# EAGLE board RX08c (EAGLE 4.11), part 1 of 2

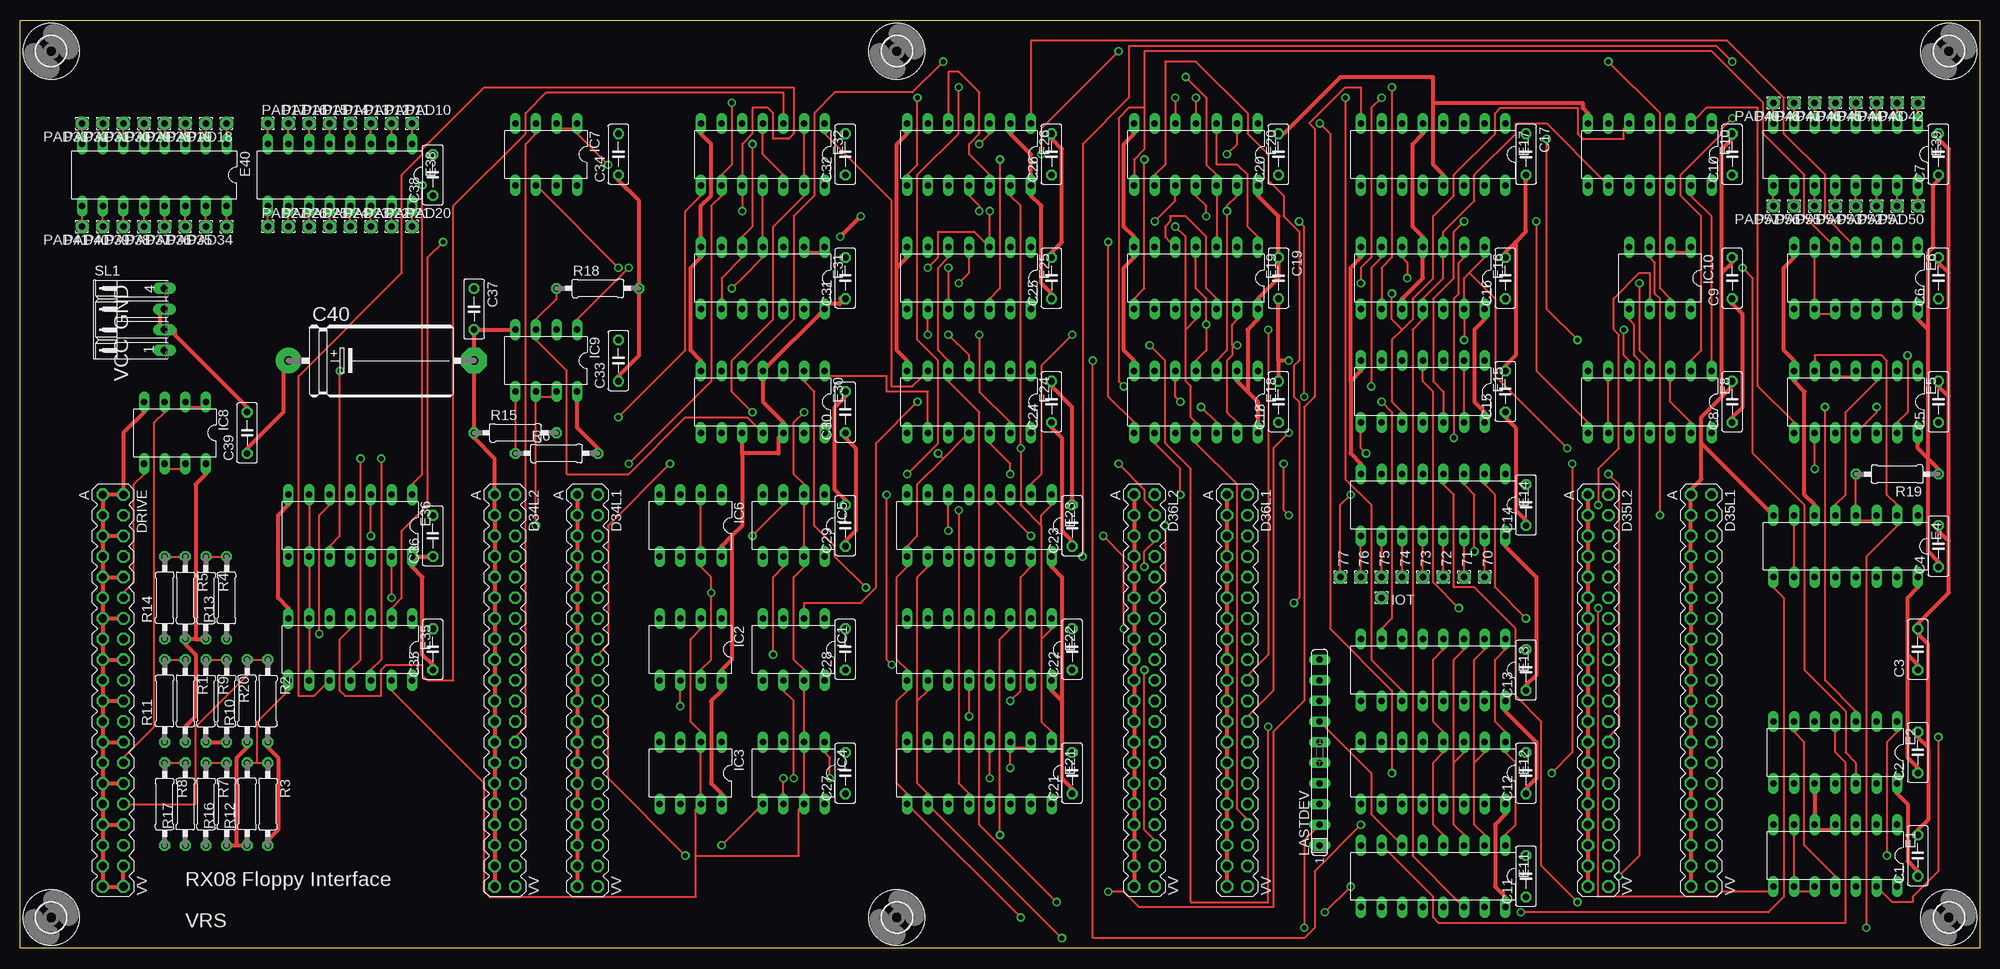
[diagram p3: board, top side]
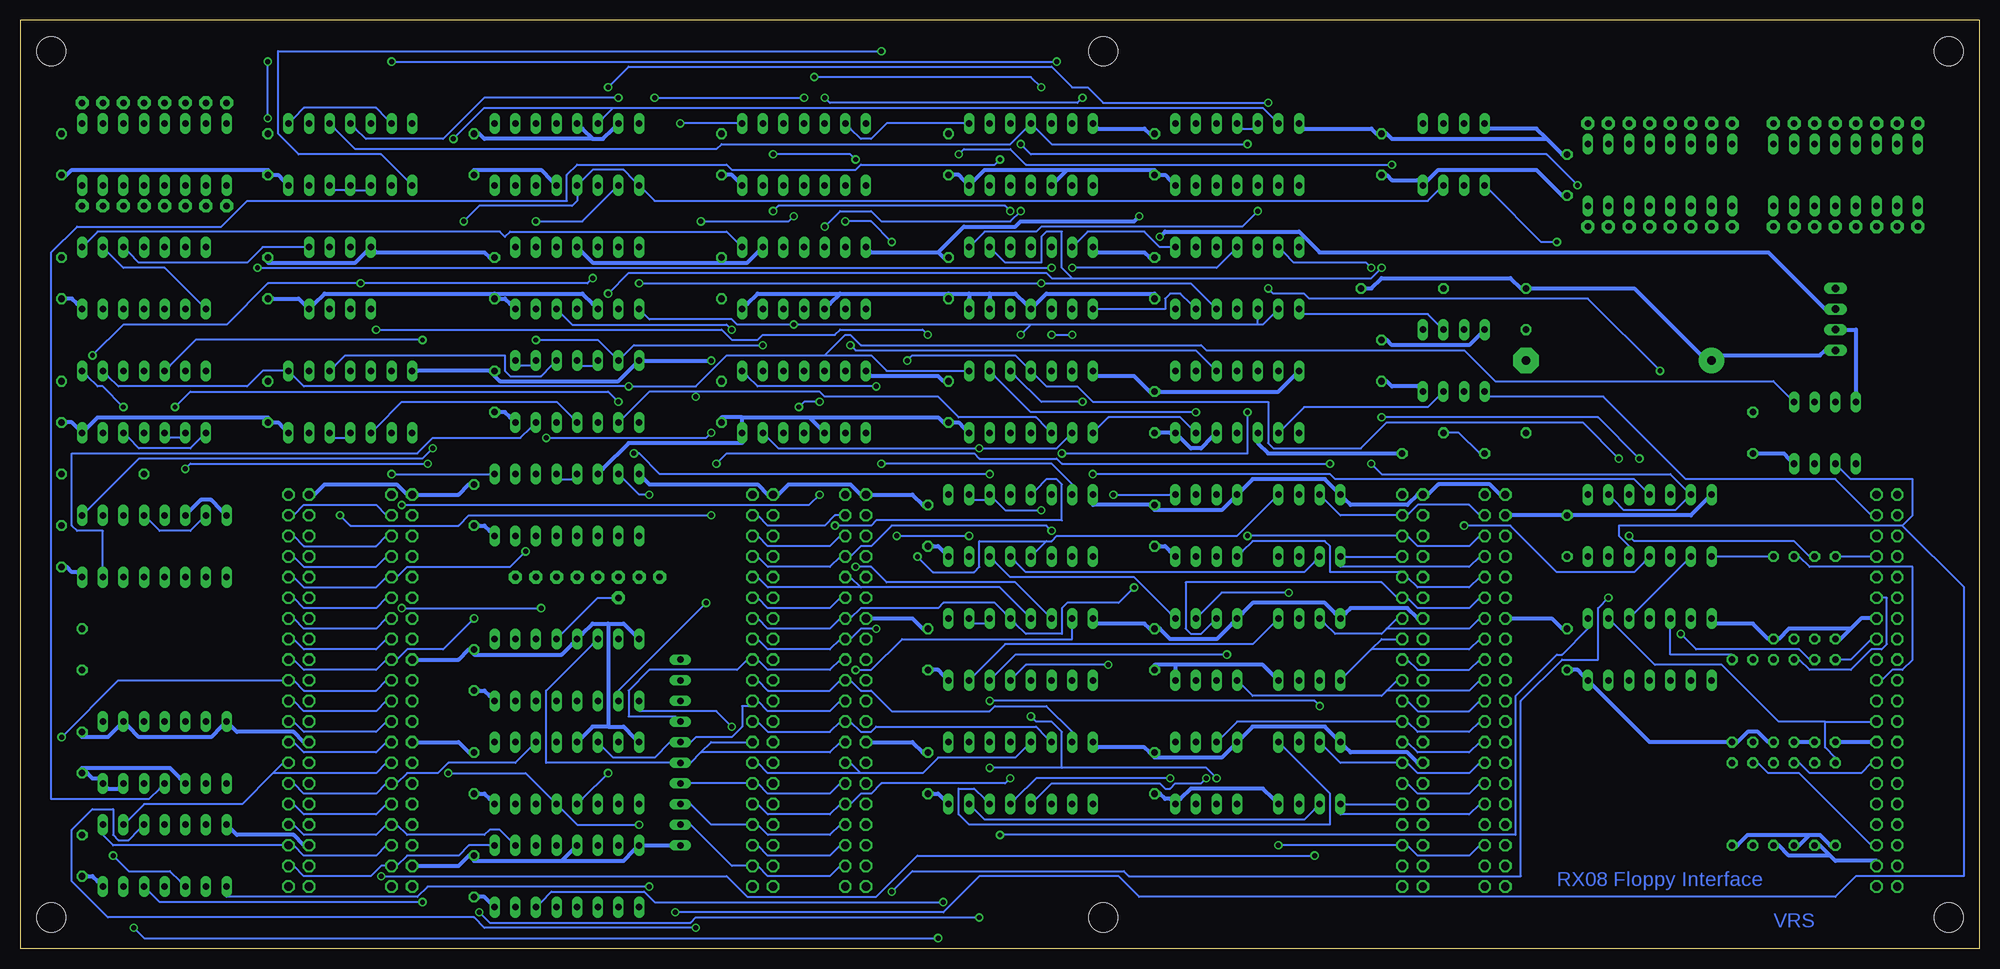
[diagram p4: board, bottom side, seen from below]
Size 241.3 x 114.3 mm. Coordinates in mm from the lower left corner, seen from the top.
Outline: 0,0 0,114.3 241.3,114.3 241.3,0 0,0
Copper layers (1*16): Top 0.035mm / dielectric 1.5mm / Bottom 0.035mm
Design rules "olimex10mil": minimum track width 10mil, minimum drill 24mil, track to track 10mil, track to pad 10mil, pad to pad 10mil, via to via 10mil, smd to smd 10mil, copper to edge 25mil, drill to drill 10mil, minimum pad ring 10mil, minimum via ring 8mil, stop-mask expansion 0mil, vias tented up to drill 0mil, thermal gap 10mil
Net classes: 1 supply: width 0.508 mm

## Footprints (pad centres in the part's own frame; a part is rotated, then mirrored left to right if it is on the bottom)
1,6/0,8 = drill 0.813 pad 1.6 octagon: 1 0,0
C050-025X075 = drill 0.813 octagon: 1 -2.54,0; 2 2.54,0
E22-9 = drill 1.016 pad 3.15 round: + -11.43,0 | drill 1.016 pad 3.15 octagon: - 11.43,0
DEC40PIN = drill 1.016 octagon: A -24.13,-1.27; AA 3.81,-1.27; B -24.13,1.27; BB 3.81,1.27; C -21.59,-1.27; CC 6.35,-1.27; D -21.59,1.27; DD 6.35,1.27; E -19.05,-1.27; EE 8.89,-1.27; F -19.05,1.27; FF 8.89,1.27; H -16.51,-1.27; HH 11.43,-1.27; J -16.51,1.27; JJ 11.43,1.27; K -13.97,-1.27; KK 13.97,-1.27; L -13.97,1.27; LL 13.97,1.27; M -11.43,-1.27; MM 16.51,-1.27; N -11.43,1.27; NN 16.51,1.27; P -8.89,-1.27; PP 19.05,-1.27; R -8.89,1.27; RR 19.05,1.27; S -6.35,-1.27; SS 21.59,-1.27; T -6.35,1.27; TT 21.59,1.27; U -3.81,-1.27; UU 24.13,-1.27; V -3.81,1.27; VV 24.13,1.27; W -1.27,-1.27; X -1.27,1.27; Y 1.27,-1.27; Z 1.27,1.27
DIL14 = drill 0.813 long: 1 -7.62,-3.81; 2 -5.08,-3.81; 3 -2.54,-3.81; 4 0,-3.81; 5 2.54,-3.81; 6 5.08,-3.81; 7 7.62,-3.81; 8 7.62,3.81; 9 5.08,3.81; 10 2.54,3.81; 11 0,3.81; 12 -2.54,3.81; 13 -5.08,3.81; 14 -7.62,3.81
DIL16 = drill 0.813 long: 1 -8.89,-3.81; 2 -6.35,-3.81; 3 -3.81,-3.81; 4 -1.27,-3.81; 5 1.27,-3.81; 6 3.81,-3.81; 7 6.35,-3.81; 8 8.89,-3.81; 9 8.89,3.81; 10 6.35,3.81; 11 3.81,3.81; 12 1.27,3.81; 13 -1.27,3.81; 14 -3.81,3.81; 15 -6.35,3.81; 16 -8.89,3.81
DIL08 = drill 0.813 long: 1 -3.81,-3.81; 2 -1.27,-3.81; 3 1.27,-3.81; 4 3.81,-3.81; 5 3.81,3.81; 6 1.27,3.81; 7 -1.27,3.81; 8 -3.81,3.81
SIL10 = drill 0.813 long: 1 -11.43,0; 2 -8.89,0; 3 -6.35,0; 4 -3.81,0; 5 -1.27,0; 6 1.27,0; 7 3.81,0; 8 6.35,0; 9 8.89,0; 10 11.43,0
0207/10 = drill 0.813 octagon: 1 -5.08,0; 2 5.08,0
04PA = drill 0.914 long: 1 -3.81,0; 2 -1.27,0; 3 1.27,0; 4 3.81,0
3,6 = hole 3.6: 0,0

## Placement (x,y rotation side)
70  [1,6/0,8]  180.34,45.72 270 top
71  [1,6/0,8]  177.8,45.72 270 top
72  [1,6/0,8]  175.26,45.72 270 top
73  [1,6/0,8]  172.72,45.72 270 top
74  [1,6/0,8]  170.18,45.72 270 top
75  [1,6/0,8]  167.64,45.72 270 top
76  [1,6/0,8]  165.1,45.72 270 top
77  [1,6/0,8]  162.56,45.72 270 top
C1  0.1  [C050-025X075]  233.68,11.43 90 top
C2  0.1  [C050-025X075]  233.68,24.13 90 top
C3  0.1  [C050-025X075]  233.68,36.83 90 top
C4  0.1  [C050-025X075]  236.22,49.53 90 top
C5  0.1  [C050-025X075]  236.22,67.31 90 top
C6  0.1  [C050-025X075]  236.22,82.55 90 top
C7  0.1  [C050-025X075]  236.22,97.79 90 top
C8  0.1  [C050-025X075]  210.82,67.31 90 top
C9  0.1  [C050-025X075]  210.82,82.55 90 top
C10  0.1  [C050-025X075]  210.82,97.79 90 top
C11  0.1  [C050-025X075]  185.42,8.89 90 top
C12  0.1  [C050-025X075]  185.42,21.59 90 top
C13  0.1  [C050-025X075]  185.42,34.29 90 top
C14  0.1  [C050-025X075]  185.42,54.61 90 top
C15  0.1  [C050-025X075]  182.88,68.58 90 top
C16  0.1  [C050-025X075]  182.88,82.55 90 top
C17  0.1  [C050-025X075]  185.42,97.79 270 top
C18  0.1  [C050-025X075]  154.94,67.31 90 top
C19  0.1  [C050-025X075]  154.94,82.55 270 top
C20  0.1  [C050-025X075]  154.94,97.79 90 top
C21  0.1  [C050-025X075]  129.54,21.59 90 top
C22  0.1  [C050-025X075]  129.54,36.83 90 top
C23  0.1  [C050-025X075]  129.54,52.07 90 top
C24  0.1  [C050-025X075]  127,67.31 90 top
C25  0.1  [C050-025X075]  127,82.55 90 top
C26  0.1  [C050-025X075]  127,97.79 90 top
C27  0.1  [C050-025X075]  101.6,21.59 90 top
C28  0.1  [C050-025X075]  101.6,36.83 90 top
C29  0.1  [C050-025X075]  101.6,52.07 90 top
C30  0.1  [C050-025X075]  101.6,66.04 90 top
C31  0.1  [C050-025X075]  101.6,82.55 90 top
C32  0.1  [C050-025X075]  101.6,97.79 90 top
C33  0.1  [C050-025X075]  73.66,72.39 90 top
C34  0.1  [C050-025X075]  73.66,97.79 90 top
C35  0.1  [C050-025X075]  50.8,36.83 90 top
C36  0.1  [C050-025X075]  50.8,50.8 90 top
C37  0.1  [C050-025X075]  55.88,78.74 270 top
C38  0.1  [C050-025X075]  50.8,95.25 90 top
C39  0.1  [C050-025X075]  27.94,63.5 90 top
C40  100uf  [E22-9]  44.45,72.39 0 top
D34L1  [DEC40PIN]  69.85,31.75 270 top
D34L2  [DEC40PIN]  59.69,31.75 270 top
D35L1  [DEC40PIN]  207.01,31.75 270 top
D35L2  [DEC40PIN]  194.31,31.75 270 top
D36L1  [DEC40PIN]  149.86,31.75 270 top
D36L2  [DEC40PIN]  138.43,31.75 270 top
DRIVE  [DEC40PIN]  11.43,31.75 270 top
E1  74LS10N  [DIL14]  223.52,11.43 180 top
E2  74LS74N  [DIL14]  223.52,24.13 180 top
E4  74LS161N  [DIL16]  224.79,49.53 180 top
E5  74LS00N  [DIL14]  226.06,67.31 180 top
E6  74LS00N  [DIL14]  226.06,82.55 180 top
E8  74LS10N  [DIL14]  200.66,67.31 180 top
E10  74LS10N  [DIL14]  200.66,97.79 180 top
E11  74LS138N  [DIL16]  173.99,8.89 180 top
E12  74LS138N  [DIL16]  173.99,21.59 180 top
E13  74LS138N  [DIL16]  173.99,34.29 180 top
E14  74LS138N  [DIL16]  173.99,54.61 180 top
E15  74LS00N  [DIL14]  172.72,68.58 180 top
E16  74LS74N  [DIL14]  172.72,82.55 180 top
E17  74LS76N  [DIL16]  173.99,97.79 180 top
E18  74LS74N  [DIL14]  144.78,67.31 180 top
E19  74LS74N  [DIL14]  144.78,82.55 180 top
E20  74HCT32N  [DIL14]  144.78,97.79 180 top
E21  74LS195N  [DIL16]  118.11,21.59 180 top
E22  74LS195N  [DIL16]  118.11,36.83 180 top
E23  74LS195N  [DIL16]  118.11,52.07 180 top
E24  74LS08N  [DIL14]  116.84,67.31 180 top
E25  74LS04N  [DIL14]  116.84,82.55 180 top
E26  74LS74N  [DIL14]  116.84,97.79 180 top
E30  74LS74N  [DIL14]  91.44,67.31 180 top
E31  74LS20N  [DIL14]  91.44,82.55 180 top
E32  74LS27N  [DIL14]  91.44,97.79 180 top
E35  74HCT02N  [DIL14]  40.64,36.83 180 top
E36  74HCT02N  [DIL14]  40.64,52.07 180 top
E38  SPARE  [DIL16]  39.37,95.25 180 top
E39  SPARE  [DIL16]  224.79,97.79 180 top
E40  SPARE  [DIL16]  16.51,95.25 180 top
IC1  DS75452N  [DIL08]  95.25,36.83 180 top
IC2  DS75452N  [DIL08]  82.55,36.83 180 top
IC3  DS75452N  [DIL08]  82.55,21.59 180 top
IC4  DS75452N  [DIL08]  95.25,21.59 180 top
IC5  DS75452N  [DIL08]  95.25,52.07 180 top
IC6  DS75452N  [DIL08]  82.55,52.07 180 top
IC7  DS75452N  [DIL08]  64.77,97.79 180 top
IC8  DS75452N  [DIL08]  19.05,63.5 180 top
IC9  DS75452N  [DIL08]  64.77,72.39 180 top
IC10  DS75452N  [DIL08]  201.93,82.55 180 top
IOT  [1,6/0,8]  167.64,43.18 270 top
LASTDEV  100  [SIL10]  160.02,24.13 90 top
PAD10  [1,6/0,8]  48.26,101.6 0 top
PAD11  [1,6/0,8]  45.72,101.6 0 top
PAD12  [1,6/0,8]  43.18,101.6 0 top
PAD13  [1,6/0,8]  40.64,101.6 0 top
PAD14  [1,6/0,8]  38.1,101.6 0 top
PAD15  [1,6/0,8]  35.56,101.6 0 top
PAD16  [1,6/0,8]  33.02,101.6 0 top
PAD17  [1,6/0,8]  30.48,101.6 0 top
PAD18  [1,6/0,8]  25.4,101.6 180 top
PAD19  [1,6/0,8]  22.86,101.6 180 top
PAD20  [1,6/0,8]  48.26,88.9 0 top
PAD21  [1,6/0,8]  45.72,88.9 0 top
PAD22  [1,6/0,8]  43.18,88.9 0 top
PAD23  [1,6/0,8]  40.64,88.9 0 top
PAD24  [1,6/0,8]  38.1,88.9 0 top
PAD25  [1,6/0,8]  35.56,88.9 0 top
PAD26  [1,6/0,8]  33.02,88.9 0 top
PAD27  [1,6/0,8]  30.48,88.9 0 top
PAD28  [1,6/0,8]  20.32,101.6 180 top
PAD29  [1,6/0,8]  17.78,101.6 180 top
PAD30  [1,6/0,8]  15.24,101.6 180 top
PAD31  [1,6/0,8]  12.7,101.6 180 top
PAD32  [1,6/0,8]  10.16,101.6 180 top
PAD33  [1,6/0,8]  7.62,101.6 180 top
PAD34  [1,6/0,8]  25.4,88.9 180 top
PAD35  [1,6/0,8]  22.86,88.9 180 top
PAD36  [1,6/0,8]  20.32,88.9 180 top
PAD37  [1,6/0,8]  17.78,88.9 180 top
PAD38  [1,6/0,8]  15.24,88.9 180 top
PAD39  [1,6/0,8]  12.7,88.9 180 top
PAD40  [1,6/0,8]  10.16,88.9 180 top
PAD41  [1,6/0,8]  7.62,88.9 180 top
PAD42  [1,6/0,8]  233.68,104.14 180 top
PAD43  [1,6/0,8]  231.14,104.14 180 top
PAD44  [1,6/0,8]  228.6,104.14 180 top
PAD45  [1,6/0,8]  226.06,104.14 180 top
PAD46  [1,6/0,8]  223.52,104.14 180 top
PAD47  [1,6/0,8]  220.98,104.14 180 top
PAD48  [1,6/0,8]  218.44,104.14 180 top
PAD49  [1,6/0,8]  215.9,104.14 180 top
PAD50  [1,6/0,8]  233.68,91.44 180 top
PAD51  [1,6/0,8]  231.14,91.44 180 top
PAD52  [1,6/0,8]  228.6,91.44 180 top
PAD53  [1,6/0,8]  226.06,91.44 180 top
PAD54  [1,6/0,8]  223.52,91.44 180 top
PAD55  [1,6/0,8]  220.98,91.44 180 top
PAD56  [1,6/0,8]  218.44,91.44 180 top
PAD57  [1,6/0,8]  215.9,91.44 180 top
R1  180  [0207/10]  20.32,30.48 270 top
R2  180  [0207/10]  30.48,30.48 270 top
R3  180  [0207/10]  30.48,17.78 270 top
R4  180  [0207/10]  22.86,43.18 270 top
R5  180  [0207/10]  20.32,43.18 270 top
R6  180  [0207/10]  66.04,60.96 0 top
R7  180  [0207/10]  22.86,17.78 270 top
R8  180  [0207/10]  17.78,17.78 270 top
R9  390  [0207/10]  22.86,30.48 270 top
R10  390  [0207/10]  27.94,30.48 90 top
R11  390  [0207/10]  17.78,30.48 90 top
R12  390  [0207/10]  27.94,17.78 90 top
R13  390  [0207/10]  25.4,43.18 90 top
R14  390  [0207/10]  17.78,43.18 90 top
R15  390  [0207/10]  60.96,63.5 0 top
R16  390  [0207/10]  25.4,17.78 90 top
R17  390  [0207/10]  20.32,17.78 90 top
R18  10K  [0207/10]  71.12,81.28 0 top
R19  10K  [0207/10]  231.14,58.42 180 top
R20  180  [0207/10]  25.4,30.48 270 top
SL1  [04PA]  17.78,77.47 90 top
U$1  [3,6]  237.49,3.81 0 top
U$2  [3,6]  237.49,110.49 0 top
U$3  [3,6]  3.81,110.49 0 top
U$4  [3,6]  3.81,3.81 0 top
U$5  [3,6]  107.95,110.49 0 top
U$6  [3,6]  107.95,3.81 0 top

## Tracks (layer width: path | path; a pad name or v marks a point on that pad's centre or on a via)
8/12  (via drill 0.61)
  Top 0.254: v170.81,82.55 170.81,84.45 170.18,85.09 E16.5 | v199.39,81.92 199.39,73.66 200.66,72.39 E8.4 | v232.41,73.03 232.41,66.04 231.14,64.77 E5.13
  Bottom 0.254: v170.81,82.55 171.45,81.92 v199.39,81.92 210.82,81.92 215.9,76.83 228.6,76.83 v232.41,73.03
8/12\  (via drill 0.61)
  Top 0.254: IC8.2 20.95,66.67 22.23,66.67 IC8.1 | v166.37,69.22 166.37,83.82 167.64,85.09 E16.6 | E10.13 205.74,92.71 208.28,90.17 208.28,72.39 E8.1
  Bottom 0.254: 142.24,73.03 154.31,73.03 158.12,69.22 v166.37,69.22 206.38,69.22 207.65,70.48 E8.1 208.91,71.12 211.46,71.12 213.36,69.22 229.24,69.22 230.5,70.48 E5.2 | 142.24,73.03 136.53,73.03 134.62,71.12 125.09,71.12 E24.1 | 142.24,73.03 139.7,75.56 139.06,75.56 137.79,74.3 95.89,74.3 95.25,73.66 63.5,73.66 59.69,69.85 25.4,69.85 23.5,67.94 IC8.1
ACB00\
  Bottom 0.254: IC6.3 80.64,55.24 78.74,53.34 71.75,53.34 D34L1.D 70.48,53.34 69.22,54.61 62.87,54.61 61.59,53.34 D34L2.D
ACB01\
  Bottom 0.254: D34L1.J 71.75,48.26 78.11,48.26 IC6.5 78.74,46.99 62.87,46.99 61.59,48.26 D34L2.J
ACB02\
  Bottom 0.254: IC1.3 94.61,40.01 95.89,38.73 97.16,38.73 97.79,39.37 97.79,45.09 73.66,45.09 71.75,43.18 D34L1.N 70.48,43.18 69.22,41.91 62.87,41.91 61.59,43.18 D34L2.N
ACB03\
  Bottom 0.254: 74.93,36.83 73.66,38.1 71.75,38.1 D34L1.T | 74.93,36.83 78.11,33.66 IC2.5 | 74.93,36.83 62.87,36.83 61.59,38.1 D34L2.T
ACB04\
  Bottom 0.254: 73.03,31.75 71.75,33.02 D34L1.X | 73.03,31.75 73.66,31.11 89.53,31.11 90.81,32.38 IC1.5 | 73.03,31.75 62.87,31.75 61.59,33.02 D34L2.X
ACB05\
  Bottom 0.254: IC4.3 93.34,26.04 91.44,27.94 71.75,27.94 D34L1.BB 70.48,27.94 69.22,26.67 62.87,26.67 61.59,27.94 D34L2.BB
ACB06\
  Bottom 0.254: IC3.3 80.64,24.77 78.74,22.86 71.75,22.86 D34L1.FF 70.48,22.86 69.22,21.59 62.87,21.59 61.59,22.86 D34L2.FF
ACB07\
  Bottom 0.254: D34L1.LL 71.75,17.78 78.11,17.78 IC3.5 78.74,16.51 62.87,16.51 61.59,17.78 D34L2.LL
ACB08\  (via drill 0.61)
  Top 0.254: v86.36,12.7 90.81,17.14 IC4.5
  Bottom 0.254: v86.36,12.7 71.75,12.7 D34L1.RR 70.48,12.7 69.22,11.43 62.87,11.43 61.59,12.7 D34L2.RR
ACB09\  (via drill 0.61)
  Top 0.254: v90.17,50.8 93.98,54.61 IC5.3
  Bottom 0.254: v90.17,50.8 71.75,50.8 D34L1.F 70.48,50.8 69.22,49.53 62.87,49.53 61.59,50.8 D34L2.F
ACB10\
  Bottom 0.254: IC5.5 90.81,48.9 89.53,50.16 80.64,50.16 80.01,49.53 80.01,46.35 71.12,46.35 D34L1.L 70.48,45.72 69.22,44.45 62.87,44.45 61.59,45.72 D34L2.L
ACB11\
  Bottom 0.254: 73.03,39.37 71.75,40.64 D34L1.R | 73.03,39.37 73.66,38.73 79.38,38.73 80.64,40.01 IC2.3 | 73.03,39.37 62.87,39.37 61.59,40.64 D34L2.R
ACCLEAR\
  Top 0.254: IC7.3 63.5,100.33 62.23,99.06 62.23,27.3 60.96,26.04 D34L2.DD
  Bottom 0.254: D34L1.DD 70.48,25.4 69.22,24.13 62.87,24.13 61.59,25.4 D34L2.DD
BAC00  (via drill 0.61)
  Top 0.254: v135.25,59.69 138.43,56.52 138.43,55.24 139.7,53.98 D36L2.D
  Bottom 0.254: v135.25,59.69 114.3,59.69 111.76,57.15 E23.7 | D36L1.D 150.5,53.34 149.22,52.07 142.24,52.07 140.97,53.34 140.34,53.34 D36L2.D
BAC01  (via drill 0.61)
  Top 0.254: v114.3,51.44 114.3,54.61 E23.6
  Bottom 0.254: v114.3,51.44 114.94,52.07 133.99,52.07 136.53,49.53 137.79,49.53 139.06,48.26 D36L2.J 140.34,48.26 141.6,46.99 149.22,46.99 150.5,48.26 D36L1.J
BAC02  (via drill 0.61)
  Top 0.254: v140.97,52.07 140.97,45.09 139.7,43.81 D36L2.N
  Bottom 0.254: v140.97,52.07 136.53,52.07 135.89,52.7 113.03,52.7 113.03,57.15 113.67,57.78 114.94,57.78 116.2,56.52 E23.5 | D36L1.N 150.5,43.18 149.22,41.91 141.6,41.91 140.34,43.18 D36L2.N
BAC03  (via drill 0.61)
  Top 0.254: v124.46,50.8 120.02,55.24 E23.4 | v133.35,50.8 135.89,48.26 v135.89,39.37
  Bottom 0.254: v133.35,50.8 v124.46,50.8 | v135.89,39.37 137.79,39.37 139.06,38.1 D36L2.T 140.34,38.1 141.6,36.83 149.22,36.83 150.5,38.1 D36L1.T
BAC04  (via drill 0.61)
  Top 0.254: v153.67,76.2 153.67,36.2 151.13,33.66 D36L1.X
  Bottom 0.254: E21.7 111.76,26.67 114.94,29.84 121.28,29.84 121.92,29.21 133.99,29.21 136.53,31.75 137.79,31.75 139.06,33.02 D36L2.X 140.34,33.02 141.6,31.75 149.22,31.75 150.5,33.02 D36L1.X | v153.67,76.2 154.31,76.83 173.35,76.83 174.62,78.11 E16.12
BAC05  (via drill 0.61)
  Top 0.254: v176.53,62.87 176.53,80.01 177.16,80.64 177.16,84.45 177.8,85.09 E16.2 | v156.21,63.5 154.31,61.59 154.31,31.75 151.13,28.57 D36L1.BB
  Bottom 0.254: E21.6 114.94,26.04 116.2,27.3 135.89,27.3 136.53,26.67 137.79,26.67 139.06,27.94 D36L2.BB 140.34,27.94 141.6,26.67 149.22,26.67 150.5,27.94 D36L1.BB | v176.53,62.87 156.84,62.87 v156.21,63.5
BAC06
  Bottom 0.254: 137.79,21.59 130.18,21.59 128.27,23.5 118.75,23.5 117.47,24.77 E21.5 | 137.79,21.59 139.06,22.86 D36L2.FF | 137.79,21.59 149.22,21.59 150.5,22.86 D36L1.FF
BAC07  (via drill 0.61)
  Top 0.254: v119.38,20.95 119.38,24.13 E21.4
  Bottom 0.254: v119.38,20.95 120.02,20.32 135.25,20.32 136.53,19.05 137.79,19.05 139.06,17.78 D36L2.LL 140.34,17.78 141.6,16.51 149.22,16.51 150.5,17.78 D36L1.LL
BAC08  (via drill 0.61)
  Top 0.254: v138.43,34.29 138.43,14.61 139.7,13.34 D36L2.RR
  Bottom 0.254: v138.43,34.29 136.53,34.29 132.72,38.1 111.76,38.1 111.76,39.37 E22.7 | D36L1.RR 150.5,12.7 149.22,11.43 141.6,11.43 140.34,12.7 D36L2.RR
BAC09  (via drill 0.61)
  Top 0.254: v138.43,46.99 138.43,48.9 139.7,50.16 D36L2.F
  Bottom 0.254: v138.43,46.99 136.53,46.99 134.62,45.09 118.75,45.09 114.94,41.27 E22.6 | D36L1.F 150.5,50.8 149.22,49.53 141.6,49.53 140.34,50.8 D36L2.F
BAC10
  Bottom 0.254: 137.79,44.45 120.65,44.45 117.47,41.27 E22.5 | 137.79,44.45 139.06,45.72 D36L2.L | 137.79,44.45 149.22,44.45 150.5,45.72 D36L1.L
BAC11  (via drill 0.61)
  Top 0.254: v104.14,44.45 100.33,48.26 100.33,49.53 97.79,52.07 97.79,68.58 96.52,69.85 E30.2
  Bottom 0.254: D36L1.R 150.5,40.64 149.22,39.37 141.6,39.37 140.34,40.64 D36L2.R 139.06,40.64 137.79,41.91 128.27,41.91 127.64,42.55 121.28,42.55 120.02,41.27 E22.4 118.75,40.01 117.47,38.73 113.03,38.73 113.03,41.91 112.39,42.55 106.05,42.55 v104.14,44.45
BINIT  (via drill 0.61)
  Top 0.254: v158.12,2.54 158.12,13.34 159.38,14.61 LASTDEV.2
  Bottom 0.254: LASTDEV.2 158.75,15.24 153.67,10.16 151.76,10.16 D36L1.TT 150.5,10.16 149.22,8.89 141.6,8.89 140.34,10.16 D36L2.TT | v158.12,2.54 184.15,2.54 185.42,3.81 230.5,3.81 234.95,8.26 234.95,14.61 232.41,17.14 229.87,17.14 229.87,13.97 229.24,13.34 227.97,13.34 226.69,14.61 E1.3
BIOP1
  Top 0.254: E11.6 169.54,13.34 166.37,16.51 166.37,21.59 160.66,27.3 LASTDEV.7
  Bottom 0.254: D36L2.V 140.34,35.56 141.6,34.29 149.22,34.29 150.5,35.56 D36L1.V 151.76,35.56 153.03,34.29 163.83,34.29 166.37,31.75 166.37,28.57 160.66,28.57 LASTDEV.7
BIOP2
  Bottom 0.254: E12.6 169.54,24.77 168.28,23.5 163.19,23.5 161.29,25.4 LASTDEV.6 158.75,25.4 158.12,26.04 153.67,26.04 152.4,27.3 152.4,29.84 151.13,29.84 D36L1.Z 150.5,30.48 149.22,29.21 141.6,29.21 140.34,30.48 D36L2.Z
BIOP4
  Bottom 0.254: 157.48,24.13 156.21,25.4 151.76,25.4 D36L1.DD | 157.48,24.13 158.75,22.86 LASTDEV.5 161.29,22.86 176.53,22.86 176.53,31.75 170.81,37.47 E13.6 | 157.48,24.13 141.6,24.13 140.34,25.4 D36L2.DD
BMB00
  Bottom 0.254: D35L2.D 196.22,53.34 197.49,54.61 206.38,54.61 207.65,53.34 D35L1.D
BMB01
  Bottom 0.254: D35L2.J 196.22,48.26 197.49,46.99 206.38,46.99 207.65,48.26 D35L1.J
BMB02
  Bottom 0.254: D35L2.N 196.22,43.18 197.49,41.91 206.38,41.91 207.65,43.18 D35L1.N
BMB03  (via drill 0.61)
  Top 0.254: v236.22,26.04 236.22,9.53 233.04,6.35 233.04,5.71 230.5,5.71 229.24,6.99 E1.13
  Bottom 0.254: v236.22,26.04 229.24,33.02 208.91,33.02 D35L1.X 207.65,33.02 206.38,31.75 197.49,31.75 196.22,33.02 D35L2.X
BMB03\
  Bottom 0.254: D35L2.T 196.22,38.1 197.49,36.83 206.38,36.83 207.65,38.1 D35L1.T
BMB04
  Bottom 0.254: 210.19,21.59 208.91,22.86 D35L1.FF | 210.19,21.59 214,17.78 226.06,17.78 227.97,15.88 E1.2 | 210.19,21.59 197.49,21.59 196.22,22.86 D35L2.FF
BMB04\
  Bottom 0.254: D35L2.BB 196.22,27.94 197.49,26.67 206.38,26.67 207.65,27.94 D35L1.BB
BMB05
  Bottom 0.254: E1.1 231.14,13.97 229.87,12.7 208.91,12.7 D35L1.RR 207.65,12.7 206.38,11.43 197.49,11.43 196.22,12.7 D35L2.RR
BMB05\
  Bottom 0.254: D35L2.LL 196.22,17.78 197.49,16.51 206.38,16.51 207.65,17.78 D35L1.LL
BMB06  (via drill 0.61)
  Top 0.254: v179.07,48.9 179.07,55.88 177.8,57.15 E14.3
  Bottom 0.254: v179.07,48.9 180.97,46.99 193.68,46.99 194.94,45.72 D35L2.L 196.22,45.72 197.49,44.45 206.38,44.45 207.65,45.72 D35L1.L
BMB06\
  Bottom 0.254: D35L2.F 196.22,50.8 197.49,49.53 206.38,49.53 207.65,50.8 D35L1.F
BMB07  (via drill 0.61)
  Top 0.254: v185.42,40.64 181.61,44.45 181.61,55.88 180.34,57.15 E14.2
  Bottom 0.254: v185.42,40.64 189.23,36.83 193.68,36.83 194.94,35.56 D35L2.V 196.22,35.56 197.49,34.29 206.38,34.29 207.65,35.56 D35L1.V
BMB07\
  Bottom 0.254: D35L2.R 196.22,40.64 197.49,39.37 206.38,39.37 207.65,40.64 D35L1.R
BMB08  (via drill 0.61)
  Top 0.254: v195.58,58.42 196.85,57.15 196.85,27.3 195.58,26.04 D35L2.DD
  Bottom 0.254: v195.58,58.42 183.51,58.42 E14.1 | D35L1.DD 207.65,25.4 206.38,24.13 197.49,24.13 196.22,25.4 D35L2.DD
BMB08\
  Bottom 0.254: D35L2.Z 196.22,30.48 197.49,29.21 206.38,29.21 207.65,30.48 D35L1.Z
BMB09
  Top 0.254: 176.53,22.86 176.53,15.24 177.8,13.97 E11.3 | 176.53,22.86 177.8,24.13 E12.3 | 176.53,22.86 176.53,35.56 177.8,36.83 E13.3
  Bottom 0.254: D35L1.JJ 207.65,20.32 206.38,19.05 197.49,19.05 196.22,20.32 D35L2.JJ 194.94,20.32 193.68,21.59 189.87,21.59 188.59,22.86 180.34,22.86 178.44,24.77 E12.3
BMB10
  Top 0.254: 179.07,22.86 179.07,15.24 180.34,13.97 E11.2 | 179.07,22.86 180.34,24.13 E12.2 | 179.07,22.86 179.07,35.56 180.34,36.83 E13.2
  Bottom 0.254: D35L1.NN 207.65,15.24 206.38,13.97 197.49,13.97 196.22,15.24 D35L2.NN 194.94,15.24 193.68,13.97 184.15,13.97 183.51,14.61 182.25,14.61 180.97,13.34 E11.2
BMB11
  Top 0.254: E11.1 182.88,13.97 184.15,15.24 184.15,22.86 182.88,24.13 E12.1 182.88,26.67 181.61,27.94 181.61,35.56 182.88,36.83 E13.1
  Bottom 0.254: E11.1 183.51,12.7 186.06,12.7 187.32,11.43 193.68,11.43 194.94,10.16 D35L2.TT 196.22,10.16 196.85,10.16 198.12,8.89 206.38,8.89 207.65,10.16 D35L1.TT
BRUN\
  Bottom 0.254: D34L2.JJ 61.59,20.32 62.87,19.05 69.22,19.05 70.48,20.32 D34L1.JJ
BTS1  (via drill 0.61)
  Top 0.254: 143.51,76.2 143.51,69.85 144.15,69.22 144.15,65.41 144.78,64.77 E18.11 144.78,62.23 149.86,57.15 149.86,17.14 151.13,15.88 D36L1.NN | 143.51,76.2 144.78,77.47 E19.11 | v118.11,90.81 118.11,91.44 116.84,92.71 E26.11 | v142.24,88.9 143.51,87.63 143.51,76.2
  Bottom 0.254: LASTDEV.3 158.75,17.78 156.21,15.24 151.76,15.24 D36L1.NN 150.5,15.24 149.22,13.97 141.6,13.97 140.34,15.24 D36L2.NN | v118.11,90.81 119.38,89.53 135.25,89.53 136.53,90.81 140.34,90.81 v142.24,88.9
BTS3
  Bottom 0.254: LASTDEV.4 158.75,20.32 151.76,20.32 D36L1.JJ 150.5,20.32 149.22,19.05 141.6,19.05 140.34,20.32 D36L2.JJ
CLK_BUF  (via drill 0.61)
  Top 0.254: E5.6 220.98,72.39 220.98,73.03 229.24,73.03 229.87,72.39 229.87,55.88 231.14,54.61 E4.2 231.14,52.07 227.33,48.26 v227.33,2.54 | 110.49,30.48 110.49,20.32 111.76,19.05 E21.10 112.39,17.14 v128.27,1.27 | 110.49,30.48 111.76,31.75 E22.10 | 110.49,30.48 110.49,45.72 111.76,46.99 E23.10
  Bottom 0.254: v227.33,2.54 226.06,1.27 v128.27,1.27
CLK_PARITY\  (via drill 0.61)
  Top 0.254: E5.5 224.16,70.48 225.43,70.48 E5.4 | v191.77,74.93 187.96,78.74 v187.96,99.69
  Bottom 0.254: 168.28,103.5 88.27,103.5 87,102.23 E32.6 | 168.28,103.5 169.54,102.23 E17.6 | v191.77,74.93 219.71,74.93 222.88,71.75 E5.5 | v187.96,99.69 184.15,103.5 168.28,103.5
DONE  (via drill 0.61)
  Top 0.254: E18.3 147.32,72.39 148.59,73.66 v148.59,90.81 148.59,91.44 149.86,92.71 E20.13 | E32.11 91.44,92.71 91.44,87.63 E31.4 91.44,85.09 88.9,82.55 v87.63,81.28 | v111.76,83.82 113.03,85.09 113.03,88.27 117.47,88.27 118.75,87 E25.3 119.38,87.63 v119.38,90.81 | v39.37,71.12 39.37,50.8 38.1,49.53 E36.10
  Bottom 0.254: v111.76,83.82 93.98,83.82 92.08,85.72 E31.4 | v148.59,90.81 147.96,91.44 120.02,91.44 v119.38,90.81 | v39.37,71.12 48.26,80.01 82.55,80.01 83.19,80.64 87,80.64 v87.63,81.28
DONE\  (via drill 0.61)
  Top 0.254: v115.57,81.92 116.84,83.19 116.84,85.09 E25.4 | v167.64,104.78 166.37,103.5 166.37,85.09 165.1,83.82 v165.1,81.92
  Bottom 0.254: E31.12 94.61,79.38 97.16,81.92 v115.57,81.92 v165.1,81.92 | v167.64,104.78 184.15,104.78 189.23,99.69 198.75,99.69 200.03,100.97 E10.4
DONE_FF  (via drill 0.61)
  Top 0.254: v142.88,55.88 142.88,59.05 139.7,62.23 E18.9 | v194.31,54.61 194.31,59.05 196.85,61.59 196.85,75.56 196.22,76.2 196.22,80.01 199.39,83.19 200.66,83.19 200.66,80.01 IC10.6
  Bottom 0.254: v142.88,55.88 144.15,54.61 v194.31,54.61
DONE_SKIP\  (via drill 0.61)
  Top 0.254: v135.89,69.22 135.25,69.85 135.25,102.23 136.53,103.5 138.43,103.5 | 138.43,103.5 138.43,98.42 137.16,97.16 137.16,95.25 E20.8 | 138.43,103.5 138.43,110.49 208.28,110.49 214.63,104.14 214.63,100.33 219.71,95.25 219.71,90.17 222.88,87 E6.5
  Bottom 0.254: v135.89,69.22 150.5,69.22 151.76,70.48 E18.1
ENB_BUF_LD\  (via drill 0.61)
  Top 0.254: E32.2 96.52,100.33 96.52,95.25 E32.13 96.52,92.71 92.71,88.9 92.71,77.47 87.63,72.39 87.63,68.58 v90.17,66.04 | v184.78,4.45 215.26,4.45 217.17,6.35 217.17,43.18 215.9,44.45 E4.9 | v123.19,3.81 109.86,17.14 E21.9 109.22,19.05 107.95,20.32 107.95,30.48 109.22,31.75 E22.9 109.22,34.29 107.95,35.56 107.95,45.72 109.22,46.99 E23.9 109.22,49.53 110.49,50.8 110.49,57.15 113.67,60.33 | 113.67,60.33 116.2,62.87 E24.11 | 113.67,60.33 v113.03,60.96
  Bottom 0.254: v184.78,4.45 183.51,3.17 158.75,3.17 158.12,3.81 v123.19,3.81 | v90.17,66.04 90.17,60.96 v113.03,60.96
ERR_SKIP\
  Top 0.254: E6.4 225.43,87 222.25,90.17 222.25,95.25 217.17,100.33 217.17,104.78 210.19,111.76 124.46,111.76 124.46,102.87 E26.1
  Bottom 0.254: E26.1 125.09,101.6 134.62,101.6 136.53,99.69 137.79,99.69 139.06,100.97 E20.6
ERROR  (via drill 0.61)
  Top 0.254: v49.53,93.98 49.53,58.42 48.26,57.15 E36.1 | v118.11,99.06 119.38,100.33 E26.3
  Bottom 0.254: v49.53,93.98 53.34,97.79 116.84,97.79 v118.11,99.06
GND  (via drill 0.61)
  Top 0.508: C39.2 27.94,66.67 19.05,75.56 19.05,76.2 SL1.2 17.14,76.83 17.14,78.11 SL1.3 | 26.67,12.7 27.3,12.7 R12.1 | 26.67,12.7 26.04,12.7 R16.1 | 26.67,12.7 26.67,23.5 27.94,24.77 R10.1 | DRIVE.MM 10.16,14.61 10.16,13.34 DRIVE.PP 10.16,12.06 10.16,10.79 DRIVE.SS 10.16,9.53 10.16,8.26 DRIVE.UU 10.79,7.62 12.06,7.62 DRIVE.VV 12.7,8.26 12.7,9.53 DRIVE.TT | DRIVE.NN 12.06,15.24 10.79,15.24 DRIVE.MM | DRIVE.MM 10.16,15.88 10.16,17.14 DRIVE.KK 10.16,18.41 10.16,19.68 DRIVE.HH | DRIVE.JJ 12.06,20.32 10.79,20.32 DRIVE.HH | DRIVE.HH 10.16,20.95 10.16,22.23 DRIVE.EE 10.16,23.5 10.16,24.77 DRIVE.CC | DRIVE.CC 10.16,26.04 10.16,27.3 DRIVE.AA 10.16,28.57 10.16,29.84 DRIVE.Y | DRIVE.Z 12.06,30.48 10.79,30.48 DRIVE.Y | DRIVE.Y 10.16,31.11 10.16,32.38 DRIVE.W 10.16,33.66 10.16,34.92 DRIVE.U | DRIVE.V 12.06,35.56 10.79,35.56 DRIVE.U | DRIVE.U 10.16,36.2 10.16,37.47 DRIVE.S 10.16,38.73 10.16,40.01 DRIVE.P | DRIVE.P 10.16,41.27 10.16,42.55 DRIVE.M 10.16,43.81 10.16,45.09 DRIVE.K | DRIVE.L 12.06,45.72 10.79,45.72 DRIVE.K | DRIVE.K 10.16,46.35 10.16,47.62 DRIVE.H 10.16,48.9 10.16,50.16 DRIVE.E | DRIVE.F 12.06,50.8 10.79,50.8 DRIVE.E | DRIVE.E 10.16,51.44 10.16,52.7 DRIVE.C 10.16,53.98 10.16,55.24 DRIVE.A 10.79,55.88 12.06,55.88 DRIVE.B 12.7,56.52 12.7,63.5 15.24,66.04 IC8.4 | DRIVE.DD 12.06,25.4 10.79,25.4 DRIVE.CC | DRIVE.R 12.06,40.64 10.79,40.64 DRIVE.P | E30.7 83.82,72.39 82.55,73.66 82.55,83.82 83.82,85.09 E31.7 83.82,87.63 83.82,91.44 85.09,92.71 85.09,99.06 83.82,100.33 E32.7 | 107.95,83.82 109.22,85.09 E25.7 | 107.95,83.82 107.95,73.66 109.22,72.39 E24.7 | 107.95,83.82 107.95,99.06 109.22,100.33 E26.7
  Top 0.508: D34L1.A 68.58,55.24 68.58,53.98 D34L1.C 68.58,52.7 68.58,51.44 D34L1.E 68.58,50.16 68.58,48.9 D34L1.H 68.58,47.62 68.58,46.35 D34L1.K 68.58,45.09 68.58,43.81 D34L1.M 68.58,42.55 68.58,41.27 D34L1.P 68.58,40.01 68.58,38.73 D34L1.S 68.58,37.47 68.58,36.2 D34L1.U 68.58,34.92 68.58,33.66 D34L1.W 68.58,32.38 68.58,31.11 D34L1.Y 68.58,29.84 68.58,28.57 D34L1.AA 68.58,27.3 68.58,26.04 D34L1.CC 68.58,24.77 68.58,23.5 D34L1.EE 68.58,22.23 68.58,20.95 D34L1.HH 68.58,19.68 68.58,18.41 D34L1.KK 68.58,17.14 68.58,15.88 D34L1.MM 68.58,14.61 68.58,13.34 D34L1.PP 68.58,12.06 68.58,10.79 D34L1.SS 68.58,9.53 68.58,8.26 D34L1.UU | IC9.4 60.33,76.2 56.52,76.2 C37.2 55.88,75.56 55.88,73.66 C40.- 55.88,71.12 55.88,64.14 R15.1 55.88,62.87 58.42,60.33 58.42,56.52 D34L2.A 58.42,55.24 58.42,53.98 D34L2.C 58.42,52.7 58.42,51.44 D34L2.E 58.42,50.16 58.42,48.9 D34L2.H 58.42,47.62 58.42,46.35 D34L2.K 58.42,45.09 58.42,43.81 D34L2.M 58.42,42.55 58.42,41.27 D34L2.P 58.42,40.01 58.42,38.73 D34L2.S 58.42,37.47 58.42,36.2 D34L2.U 58.42,34.92 58.42,33.66 D34L2.W 58.42,32.38 58.42,31.11 D34L2.Y 58.42,29.84 58.42,28.57 D34L2.AA 58.42,27.3 58.42,26.04 D34L2.CC 58.42,24.77 58.42,23.5 D34L2.EE 58.42,22.23 58.42,20.95 D34L2.HH 58.42,19.68 58.42,18.41 D34L2.KK 58.42,17.14 58.42,15.88 D34L2.MM 58.42,14.61 58.42,13.34 D34L2.PP 58.42,12.06 58.42,10.79 D34L2.SS 58.42,9.53 58.42,8.26 D34L2.UU | C30.2 101.6,67.94 100.33,66.67 100.33,56.52 101.6,55.24 C29.2 | E35.7 33.02,41.91 31.75,43.18 31.75,53.34 33.02,54.61 E36.7 | 154.94,72.39 154.94,79.38 C19.2
  Top 0.508: 154.94,72.39 154.94,70.48 C18.2 | 163.83,69.85 163.83,60.96 165.1,59.69 E14.8 | 163.83,69.85 165.1,71.12 E15.7 | 163.83,69.85 163.83,83.82 165.1,85.09 E16.7 | v156.21,72.39 154.94,72.39 | D36L1.UU 148.59,8.26 148.59,9.53 D36L1.SS 148.59,10.79 148.59,12.06 D36L1.PP 148.59,13.34 148.59,14.61 D36L1.MM 148.59,15.88 148.59,17.14 D36L1.KK 148.59,18.41 148.59,19.68 D36L1.HH 148.59,20.95 148.59,22.23 D36L1.EE 148.59,23.5 148.59,24.77 D36L1.CC 148.59,26.04 148.59,27.3 D36L1.AA 148.59,28.57 148.59,29.84 D36L1.Y 148.59,31.11 148.59,32.38 D36L1.W 148.59,33.66 148.59,34.92 D36L1.U 148.59,36.2 148.59,37.47 D36L1.S 148.59,38.73 148.59,40.01 D36L1.P 148.59,41.27 148.59,42.55 D36L1.M 148.59,43.81 148.59,45.09 D36L1.K 148.59,46.35 148.59,47.62 D36L1.H 148.59,48.9 148.59,50.16 D36L1.E 148.59,51.44 148.59,52.7 D36L1.C 148.59,53.98 148.59,55.24 D36L1.A | D36L2.UU 137.16,8.26 137.16,9.53 D36L2.SS 137.16,10.79 137.16,12.06 D36L2.PP 137.16,13.34 137.16,14.61 D36L2.MM 137.16,15.88 137.16,17.14 D36L2.KK 137.16,18.41 137.16,19.68 D36L2.HH 137.16,20.95 137.16,22.23 D36L2.EE 137.16,23.5 137.16,24.77 D36L2.CC 137.16,26.04 137.16,27.3 D36L2.AA 137.16,28.57 137.16,29.84 D36L2.Y 137.16,31.11 137.16,32.38 D36L2.W 137.16,33.66 137.16,34.92 D36L2.U 137.16,36.2 137.16,37.47 D36L2.S 137.16,38.73 137.16,40.01 D36L2.P 137.16,41.27 137.16,42.55 D36L2.M 137.16,43.81 137.16,45.09 D36L2.K 137.16,46.35 137.16,47.62 D36L2.H 137.16,48.9 137.16,50.16 D36L2.E 137.16,51.44 137.16,52.7 D36L2.C 137.16,53.98 137.16,55.24 D36L2.A | C26.2 127,99.69 128.27,98.42 128.27,87 127,85.72 C25.2
  Top 0.508: E20.7 137.16,100.33 135.89,99.06 135.89,88.9 137.16,87.63 E19.7 137.16,85.09 135.89,83.82 135.89,73.66 137.16,72.39 E18.7 | C24.2 127,69.22 129.54,66.67 129.54,55.24 C23.2 | 234.95,24.77 234.95,15.88 233.68,14.61 C1.2 | 234.95,24.77 233.68,26.04 C2.2 | 234.95,24.77 234.95,37.47 233.68,38.73 C3.2 233.68,40.01 237.49,43.81 237.49,50.16 | 237.49,50.16 236.22,51.44 C4.2 | 237.49,67.94 236.22,69.22 C5.2 | 237.49,50.16 237.49,67.94 | 237.49,83.19 236.22,84.45 C6.2 | 237.49,67.94 237.49,83.19 | 237.49,83.19 237.49,98.42 236.22,99.69 C7.2 | D35L2.UU 193.04,8.26 193.04,9.53 D35L2.SS 193.04,10.79 193.04,12.06 D35L2.PP 193.04,13.34 193.04,14.61 D35L2.MM 193.04,15.88 193.04,17.14 D35L2.KK 193.04,18.41 193.04,19.68 D35L2.HH 193.04,20.95 193.04,22.23 D35L2.EE 193.04,23.5 193.04,24.77 D35L2.CC 193.04,26.04 193.04,27.3 D35L2.AA 193.04,28.57 193.04,29.84 D35L2.Y 193.04,31.11 193.04,32.38 D35L2.W 193.04,33.66 193.04,34.92 D35L2.U 193.04,36.2 193.04,37.47 D35L2.S 193.04,38.73 193.04,40.01 D35L2.P 193.04,41.27 193.04,42.55 D35L2.M 193.04,43.81 193.04,45.09 D35L2.K 193.04,46.35 193.04,47.62 D35L2.H 193.04,48.9 193.04,50.16 D35L2.E 193.04,51.44 193.04,52.7 D35L2.C 193.04,53.98 193.04,55.24 D35L2.A | 184.15,87 185.42,88.27 185.42,94.61 C17.2 | 184.15,87 182.88,85.72 C16.2 | 173.99,104.14 173.99,96.52 175.26,95.25 E17.13 | 173.99,104.14 173.99,107.31 162.56,107.31 155.57,100.33 C20.2 | 173.99,104.14 192.41,104.14 192.41,103.5 193.04,102.87 E10.7 | 184.15,87 184.15,73.03 182.88,71.75 C15.2 | D35L1.UU 205.74,8.26 205.74,9.53 D35L1.SS 205.74,10.79 205.74,12.06 D35L1.PP 205.74,13.34 205.74,14.61 D35L1.MM 205.74,15.88 205.74,17.14 D35L1.KK 205.74,18.41 205.74,19.68 D35L1.HH 205.74,20.95 205.74,22.23 D35L1.EE 205.74,23.5 205.74,24.77 D35L1.CC 205.74,26.04 205.74,27.3 D35L1.AA 205.74,28.57 205.74,29.84 D35L1.Y 205.74,31.11 205.74,32.38 D35L1.W 205.74,33.66 205.74,34.92 D35L1.U 205.74,36.2 205.74,37.47 D35L1.S 205.74,38.73 205.74,40.01 D35L1.P 205.74,41.27 205.74,42.55 D35L1.M 205.74,43.81 205.74,45.09 D35L1.K 205.74,46.35 205.74,47.62 D35L1.H 205.74,48.9 205.74,50.16 D35L1.E 205.74,51.44 205.74,52.7 D35L1.C 205.74,53.98 205.74,55.24 D35L1.A 205.74,56.52 207.01,57.78 207.01,62.23
  Top 0.508: E6.7 218.44,85.09 217.17,83.82 217.17,73.66 218.44,72.39 E5.7 218.44,69.85 219.71,68.58 219.71,55.88 220.98,54.61 E4.6 | 209.55,67.94 207.01,65.41 207.01,62.23 | 209.55,67.94 210.82,69.22 C8.2 | 209.55,83.19 210.82,84.45 C9.2 | 209.55,67.94 209.55,83.19 | 209.55,83.19 209.55,98.42 210.82,99.69 C10.2 | 207.01,62.23 215.26,53.98 E4.8 | v103.5,90.17 v100.97,87.63
  Bottom 0.508: IC8.4 15.24,68.58 15.24,76.2 16.51,76.2 SL1.2 | 18.41,11.43 17.78,10.79 12.7,10.79 DRIVE.TT | 18.41,11.43 19.68,12.7 R17.1 | E35.7 32.38,40.01 27.94,40.01 26.04,38.1 R13.1 24.77,38.1 23.5,39.37 15.88,39.37 | 15.88,39.37 14.61,40.64 13.34,40.64 DRIVE.R | 15.88,39.37 17.14,38.1 R14.1 | R11.1 17.14,25.4 13.34,25.4 DRIVE.DD | 18.41,11.43 23.5,11.43 24.77,12.7 R16.1 | E32.7 83.19,100.97 74.93,100.97 74.3,100.33 C34.2 73.03,100.33 72.39,99.69 53.34,99.69 | 53.34,99.69 54.61,100.97 60.33,100.97 IC7.4 | 53.34,99.69 51.44,97.79 C38.2 | C32.2 102.23,100.33 102.87,100.97 108.58,100.97 E26.7 | C31.2 102.23,85.09 102.87,85.72 108.58,85.72 E25.7 | E24.7 108.58,70.48 104.14,70.48 102.23,68.58 C30.2 100.97,68.58 86.36,68.58 84.45,70.48 E30.7 | E23.8 109.22,54.61 102.23,54.61 C29.2 101.6,53.98 93.34,53.98 92.08,55.24 IC5.4 90.81,56.52 89.53,57.78 80.64,57.78 79.38,56.52 IC6.4 78.11,55.24 77.47,54.61 70.48,54.61 69.22,55.88 D34L1.A 67.94,55.88 66.67,57.15 60.33,57.15 59.05,55.88 D34L2.A | E22.8 108.58,40.01 102.87,40.01 102.23,39.37 C28.2 100.97,39.37 99.69,38.1 93.98,38.1 92.08,40.01 IC1.4 90.81,41.27 89.53,42.55 80.64,42.55 79.38,41.27 IC2.4 78.11,41.27 77.47,41.91 70.48,41.91 69.22,40.64 D34L1.P | E21.8 108.58,24.77 102.87,24.77 102.23,24.13 C27.2 101.6,23.5 93.34,23.5 92.08,24.77 IC4.4 90.81,26.04 89.53,27.3 80.64,27.3 79.38,26.04 IC3.4 78.11,24.77 77.47,24.13 70.48,24.13 69.22,22.86 D34L1.EE | C33.2 73.03,74.93 72.39,74.3 62.87,74.3 61.59,75.56 IC9.4 | C35.2 51.44,39.37 52.7,40.64 57.78,40.64 D34L2.P | D34L2.C 57.78,53.34 51.44,53.34 C36.2 50.16,53.34 35.56,53.34 33.66,55.24 E36.7
  Bottom 0.508: v156.21,72.39 164.47,72.39 E15.7 165.74,71.75 167.64,69.85 182.25,69.85 182.88,70.48 C15.2 183.51,71.12 192.41,71.12 E8.7 | E14.8 164.47,57.78 163.83,57.15 150.5,57.15 149.22,55.88 D36L1.A 147.96,55.88 146.69,57.15 139.06,57.15 137.79,55.88 D36L2.A 136.53,55.88 131.44,55.88 130.18,54.61 C23.2 | C21.2 130.18,24.13 131.44,25.4 136.53,25.4 D36L2.CC | 128.27,85.72 127.64,85.09 C25.2 | 128.27,85.72 136.53,85.72 E19.7 | C24.2 127.64,69.85 128.27,70.48 136.53,70.48 E18.7 | C22.2 130.18,39.37 131.44,40.64 136.53,40.64 D36L2.P | C2.2 233.68,26.04 230.5,26.04 229.24,27.3 E2.2 227.97,27.3 226.69,26.04 217.81,26.04 216.53,27.3 E2.7 215.26,27.3 214.63,26.67 207.65,26.67 206.38,25.4 D35L1.CC | LASTDEV.1 161.29,12.7 164.47,12.7 E11.8 165.74,12.06 167,10.79 174.62,10.79 | D35L2.SS 192.41,10.16 187.32,10.16 186.06,11.43 C11.2 185.42,10.79 174.62,10.79 | 174.62,10.79 173.35,12.06 E11.5 | 168.91,27.3 170.81,27.3 172.09,26.04 E12.5 | 168.91,27.3 167,27.3 165.74,26.04 E12.8 | 168.91,40.01 170.81,40.01 172.09,38.73 E13.5 173.35,37.47 174.62,36.2 185.42,36.2 C13.2 186.06,36.83 187.32,35.56 192.41,35.56 D35L2.U | 168.91,40.01 167,40.01 165.74,38.73 E13.8 | 168.91,40.01 168.91,27.3 | C12.2 186.06,24.13 187.32,25.4 192.41,25.4 D35L2.CC | C14.2 186.06,57.15 187.32,55.88 192.41,55.88 D35L2.A 193.68,55.88 194.94,57.15 203.84,57.15 205.1,55.88 D35L1.A | E17.13 175.9,94.61 177.16,95.89 185.42,95.89 C17.2 | E1.7 215.26,14.61 214.63,13.97 207.65,13.97 206.38,12.7 D35L1.PP | C9.2 210.82,84.45 200.03,84.45 198.75,85.72 IC10.4 197.49,85.72 184.15,85.72 183.51,85.09 C16.2
  Bottom 0.508: E4.6 220.34,53.98 219.07,55.24 217.81,55.24 216.53,53.98 E4.8 | v100.97,87.63 100.33,88.27 83.82,88.27 81.28,85.72 26.04,85.72 19.05,78.74 SL1.3 | v103.5,90.17 104.14,89.53 118.11,89.53 118.75,88.9 125.09,88.9 128.27,85.72
INIT  (via drill 0.61)
  Top 0.254: IC8.6 18.41,59.05 19.68,59.05 IC8.7 | v194.31,41.91 194.31,6.35 208.91,6.35 209.55,6.99 215.26,6.99 E1.8 | v177.16,41.91 173.99,45.09 173.99,68.58 172.72,69.85 172.72,71.12 E15.4 | v160.66,4.45 v163.83,7.62
  Bottom 0.254: 9.53,52.07 44.45,52.07 44.45,50.8 43.18,49.53 E36.12 | 9.53,52.07 8.26,53.34 8.26,57.78 15.88,57.78 17.14,59.05 IC8.6 | E15.5 170.81,71.75 172.09,71.75 E15.4 | v194.31,41.91 v177.16,41.91 | 9.53,52.07 1.91,44.45 1.91,8.89 15.24,8.89 17.78,6.35 103.5,6.35 106.05,8.89 123.19,8.89 127.64,4.45 v160.66,4.45 | v163.83,7.62 191.13,7.62 192.41,6.35 215.9,6.35 E1.8
INIT1\
  Top 0.254: E11.7 168.28,12.06 173.99,6.35 173.99,3.81 174.62,3.17 224.79,3.17 224.79,22.86 223.52,24.13 223.52,26.67 E2.4
INIT4\  (via drill 0.61)
  Top 0.254: v222.25,66.67 222.25,33.02 226.06,29.21 E2.3 | v167.64,67.31 168.91,66.04 168.91,40.64 167.64,39.37 E13.7
  Bottom 0.254: v222.25,66.67 220.34,68.58 168.91,68.58 v167.64,67.31
INIT\  (via drill 0.61)
  Top 0.254: v177.8,74.93 177.8,77.47 E16.13 177.8,80.01 177.8,82.55 178.44,83.19 | 178.44,83.19 180.34,85.09 E16.1 | v190.5,61.59 181.61,70.48 181.61,80.01 178.44,83.19 | E30.1 99.69,70.48 106.68,70.48 106.68,68.58 111.76,68.58 111.76,64.77 E24.9 | 149.22,74.3 149.22,73.03 148.59,72.39 148.59,66.04 149.86,64.77 E18.13 | 149.22,74.3 149.22,76.83 149.86,77.47 E19.13 | 125.73,38.1 125.73,27.94 127,26.67 E21.1 | 125.73,38.1 127,39.37 E22.1 | 125.73,52.07 125.73,38.1 | 125.73,52.07 125.73,53.34 127,54.61 E23.1 | 125.73,52.07 123.19,54.61 v123.19,61.59 123.19,91.44 121.92,92.71 E26.13 | v149.86,74.3 149.22,74.3
  Bottom 0.254: v177.8,74.93 170.18,74.93 168.28,73.03 E15.6 167,73.03 165.74,74.3 v149.86,74.3 | v190.5,61.59 191.77,60.33 226.69,60.33 233.04,53.98 E4.1 | E24.9 112.39,62.87 113.67,61.59 v123.19,61.59 147.96,61.59 149.22,62.87 E18.13
INT_RQ\  (via drill 0.61)
  Top 0.254: v196.85,8.89 199.39,11.43 199.39,72.39 198.75,73.03 198.75,76.83 198.12,77.47 IC10.5 | v81.92,11.43 72.39,20.95 72.39,28.57 71.12,29.84 D34L1.Z
  Bottom 0.254: v196.85,8.89 154.31,8.89 151.76,6.35 135.89,6.35 130.81,11.43 v81.92,11.43 | D34L2.Z 61.59,30.48 62.87,29.21 69.22,29.21 70.48,30.48 D34L1.Z
INTR4\  (via drill 0.61)
  Top 0.254: v139.06,74.3 140.97,72.39 140.97,62.23 144.15,59.05 144.15,5.71 153.67,5.71 v153.67,27.3
  Bottom 0.254: v139.06,74.3 138.43,73.66 96.52,73.66 94.61,71.75 E30.3 | v153.67,27.3 155.57,29.21 165.1,29.21 E13.9
IOS\  (via drill 0.61)
  Top 0.254: v201.93,53.34 201.93,80.01 201.29,80.64 201.29,84.45 200.66,85.09 IC10.3 | v156.21,53.34 155.57,53.98 v155.57,59.69 | v80.01,59.69 72.39,52.07 72.39,37.47 71.12,36.2 D34L1.V
  Bottom 0.254: v201.93,53.34 200.66,52.07 187.32,52.07 186.06,53.34 v156.21,53.34 | v155.57,59.69 154.31,60.96 123.83,60.96 123.19,60.33 113.67,60.33 113.03,59.69 v80.01,59.69 | D34L2.V 61.59,35.56 62.87,34.29 69.22,34.29 70.48,35.56 D34L1.V
LCD1
  Top 0.254: E31.2 97.16,85.72 98.42,85.72 E31.1
  Bottom 0.254: E25.6 111.12,87 109.86,88.27 102.87,88.27 100.97,86.36 99.69,86.36 E31.1
LCD1\  (via drill 0.61)
  Top 0.254: E25.5 114.3,85.09 113.03,83.82 113.03,73.66 114.3,72.39 E24.5 114.3,69.85 118.11,66.04 118.11,15.24 v127.64,5.71 | E11.14 177.16,5.71 171.45,11.43 171.45,76.2 172.72,77.47 E16.11 172.72,80.01 175.26,82.55 175.26,85.09 E16.3 175.26,87.63 175.26,88.27 179.07,92.08 179.07,95.25 184.15,100.33 184.15,101.6 187.96,101.6 194.94,94.61 E10.9
  Bottom 0.254: v127.64,5.71 163.19,5.71 164.47,6.99 175.9,6.99 177.16,5.71 E11.14
MAINT  (via drill 0.61)
  Top 0.254: E35.9 35.56,34.29 35.56,39.37 E35.6 35.56,41.91 35.56,46.99 E36.9 35.56,49.53 35.56,54.61 E36.6 | v74.93,59.69 85.09,69.85 85.09,91.44 86.36,92.71 E32.9 86.36,95.25 87.63,96.52 v87.63,104.14 | v168.91,106.05 168.91,85.09 167.64,83.82 167.64,80.01 E16.9
  Bottom 0.254: E35.3 42.55,41.27 36.2,47.62 E36.9 | E36.2 45.09,55.24 43.81,53.98 37.47,53.98 36.2,55.24 E36.6 36.2,56.52 38.1,58.42 73.66,58.42 v74.93,59.69 | v168.91,106.05 166.37,108.58 114.3,108.58 111.76,106.05 109.86,106.05 107.95,104.14 v87.63,104.14
MAINT\  (via drill 0.61)
  Top 0.254: E18.4 144.78,72.39 146.05,73.66 v146.05,76.83 146.05,80.01 144.78,81.28 144.78,85.09 E19.4 | v118.11,75.56 118.11,68.58 121.92,64.77 E24.13 | E31.9 86.36,80.01 86.36,82.55 88.9,85.09 E31.5 88.9,87.63 90.17,88.9 v90.17,99.06
  Bottom 0.254: 116.84,76.83 v118.11,75.56 | 88.9,76.83 88.27,76.83 87,78.11 E31.9 | 88.9,76.83 116.84,76.83 | 116.84,76.83 v146.05,76.83 153.03,76.83 153.67,77.47 163.83,77.47 164.47,78.11 E16.8 | v90.17,99.06 114.3,99.06 116.2,100.97 E26.4 117.47,100.97 119.38,99.06 154.94,99.06 155.57,98.42 200.03,98.42 202.56,100.97 E10.3 | 88.9,76.83 88.9,77.47 E31.10
MSB8  (via drill 0.61)
  Top 0.254: v95.25,20.95 95.25,30.48 93.98,31.75 IC1.6 | v197.49,76.2 197.49,73.03 198.12,72.39 E8.5 | v129.54,75.56 125.73,71.75 125.73,58.42 124.46,57.15 E23.2 | v115.57,53.98 115.57,20.32 116.84,19.05 E21.12
  Bottom 0.254: v95.25,20.95 95.89,20.32 99.06,20.32 99.69,19.68 100.33,19.68 100.97,20.32 114.3,20.32 116.2,18.41 E21.12 | E23.2 123.83,55.24 122.56,55.24 E23.3 121.28,55.24 120.02,53.98 v115.57,53.98 | v197.49,76.2 154.94,76.2 153.67,74.93 150.5,74.93 149.86,75.56 140.97,75.56 140.34,76.2 130.18,76.2 v129.54,75.56
MSB12  (via drill 0.61)
  Top 0.254: v210.82,102.23 209.55,100.97 209.55,100.33 204.47,95.25 204.47,92.71 207.01,90.17 207.01,73.66 205.74,72.39 E8.2 | v210.82,109.22 208.91,111.12 136.53,111.12 136.53,104.78 130.81,99.06 v130.81,48.26
  Bottom 0.254: 114.94,50.16 114.3,50.16 113.67,50.8 91.44,50.8 87,55.24 IC6.1 | 114.94,50.16 116.2,48.9 E23.12 | v210.82,102.23 v210.82,109.22 | v130.81,48.26 128.91,46.35 123.83,46.35 123.19,46.99 123.19,50.16 114.94,50.16
MYDEV\
  Top 0.254: E11.4 175.26,13.97 173.99,15.24 173.99,22.86 175.26,24.13 E12.4 175.26,26.67 173.99,27.94 173.99,35.56 175.26,36.83 E13.4
  Bottom 0.254: E13.4 174.62,38.73 170.18,43.18 168.28,43.18 IOT.1
N$1
  Top 0.254: E14.9 165.1,49.53 165.1,46.35 76.1
N$2
  Bottom 0.254: IC1.1 99.69,41.27 104.14,45.72 119.38,45.72 121.28,47.62 E23.14
N$3  (via drill 0.61)
  Top 0.254: 83.19,11.43 83.19,17.14 IC3.7 83.82,19.05 83.82,24.13 IC3.2 83.82,26.67 82.55,27.94 82.55,38.1 83.82,39.37 IC2.2 | 83.19,11.43 83.19,6.35 57.78,6.35 57.15,6.99 57.15,20.32 45.72,31.75 E35.13 | v96.52,66.04 95.25,64.77 95.25,58.42 96.52,57.15 IC5.2 96.52,54.61 96.52,49.53 IC5.7 96.52,46.99 95.25,45.72 95.25,35.56 96.52,34.29 IC1.7 96.52,31.75 96.52,26.67 IC4.2 96.52,24.13 96.52,19.05 IC4.7 95.89,17.14 95.89,11.43 83.19,11.43
  Bottom 0.254: v96.52,66.04 116.84,66.04 121.28,70.48 E24.2
N$4  (via drill 0.61)
  Top 0.254: v41.91,60.33 41.91,35.56 40.64,34.29 E35.11 | v73.66,65.41 81.92,73.66 81.92,90.81 83.82,92.71 E32.8
  Bottom 0.254: v41.91,60.33 46.99,65.41 v73.66,65.41
N$5
  Top 0.254: E14.15 180.34,49.53 180.34,46.35 70.1
N$6
  Top 0.254: E14.14 177.8,49.53 177.8,46.35 71.1
N$7
  Top 0.254: E14.13 175.26,49.53 175.26,46.35 72.1
N$8
  Top 0.254: E14.12 172.72,49.53 172.72,46.35 73.1
N$9
  Top 0.254: E14.11 170.18,49.53 170.18,46.35 74.1
N$10
  Top 0.254: E14.10 167.64,49.53 167.64,46.35 75.1
N$11  (via drill 0.61)
  Top 0.254: v163.83,55.88 162.56,54.61 162.56,46.35 77.1
  Bottom 0.254: v163.83,55.88 165.1,55.88 167,57.78 E14.7
N$12  (via drill 0.61)
  Top 0.254: IC2.7 83.82,34.29 85.09,35.56 v85.09,43.81 85.09,45.72 83.82,46.99 IC6.7 83.82,49.53 83.82,54.61 IC6.2 | v110.49,67.31 105.41,62.23 105.41,44.45 103.5,42.55 96.52,42.55 96.52,41.91 IC1.2
  Bottom 0.254: v85.09,43.81 93.34,43.81 95.89,41.27 IC1.2 | v110.49,67.31 115.57,67.31 118.75,70.48 E24.3
N$13
  Top 0.254: E38.1 48.26,100.33 48.26,100.97 PAD10.1
N$14
  Top 0.254: E38.2 45.72,100.33 45.72,100.97 PAD11.1
N$15
  Top 0.254: E38.3 43.18,100.33 43.18,100.97 PAD12.1
N$16
  Top 0.254: E38.4 40.64,100.33 40.64,100.97 PAD13.1
N$17
  Top 0.254: E38.5 38.1,100.33 38.1,100.97 PAD14.1
N$18
  Top 0.254: E38.6 35.56,100.33 35.56,100.97 PAD15.1
N$19
  Top 0.254: E38.7 33.02,100.33 33.02,100.97 PAD16.1
N$20
  Top 0.254: E38.8 30.48,100.33 30.48,100.97 PAD17.1
N$21
  Top 0.254: E4.5 223.52,54.61 224.79,55.88 224.79,66.04 228.6,69.85 E5.3
N$22  (via drill 0.61)
  Top 0.254: v146.05,90.17 146.05,91.44 144.78,92.71 E20.11 | v157.48,89.53 158.12,88.9 v158.12,67.94
  Bottom 0.254: 158.12,68.58 163.83,68.58 167,65.41 E15.9 | 158.12,68.58 142.88,68.58 142.24,67.94 128.27,67.94 125.73,65.41 116.2,65.41 114.94,64.14 E24.10 | v146.05,90.17 146.69,89.53 v157.48,89.53 | 158.12,68.58 v158.12,67.94
N$23
  Top 0.254: E38.16 48.26,90.17 48.26,89.53 PAD20.1
N$24
  Top 0.254: E38.15 45.72,90.17 45.72,89.53 PAD21.1
N$25
  Top 0.254: E38.14 43.18,90.17 43.18,89.53 PAD22.1
N$26
  Top 0.254: E38.13 40.64,90.17 40.64,89.53 PAD23.1
N$27
  Top 0.254: E38.12 38.1,90.17 38.1,89.53 PAD24.1
N$28
  Top 0.254: E38.11 35.56,90.17 35.56,89.53 PAD25.1
N$29
  Top 0.254: E38.10 33.02,90.17 33.02,89.53 PAD26.1
N$30
  Top 0.254: E38.9 30.48,90.17 30.48,89.53 PAD27.1
N$31  (via drill 0.61)
  Top 0.254: v93.98,20.95 93.98,19.05 IC4.6 | v121.92,22.23 121.92,24.13 E21.3 122.56,24.77 123.83,24.77 E21.2 | v116.84,28.57 116.84,31.75 E22.12
  Bottom 0.254: v93.98,20.95 95.25,22.23 113.03,22.23 | 113.03,22.23 v121.92,22.23 | v116.84,28.57 116.2,27.94 114.3,27.94 113.03,26.67 113.03,22.23
N$32  (via drill 0.61)
  Top 0.254: v121.92,58.42 121.92,59.69 119.38,62.23 E24.12 | v165.74,60.96 165.1,61.59 165.1,63.5 E15.8
  Bottom 0.254: v121.92,58.42 162.56,58.42 165.1,60.96 v165.74,60.96
N$33
  Bottom 0.254: IC6.6 81.92,47.62 83.19,46.35 117.47,46.35 118.75,47.62 E23.13
N$34
  Top 0.254: E40.1 25.4,100.33 25.4,100.97 PAD18.1
N$35  (via drill 0.61)
  Top 0.254: v228.6,66.67 228.6,66.04 226.69,64.14 E5.11
  Bottom 0.254: v228.6,66.67 231.14,69.22 231.78,69.22 233.04,70.48 E5.1
N$36  (via drill 0.61)
  Top 0.254: E1.10 220.34,6.99 219.07,6.99 E1.9 218.44,8.89 218.44,13.97 E1.6 | v229.87,11.43 229.87,25.4 231.14,26.67 E2.1
  Bottom 0.254: v229.87,11.43 227.97,9.53 222.88,9.53 221.62,8.26 E1.10
N$37
  Top 0.254: E8.13 205.74,64.77 203.2,67.31 203.2,69.85 E8.3
  Bottom 0.254: E15.3 175.9,71.75 177.16,70.48 180.97,70.48 181.61,71.12 181.61,73.03 201.29,73.03 202.56,71.75 E8.3
N$38
  Bottom 0.254: E8.11 201.29,62.87 202.56,62.87 E8.12
N$39
  Top 0.254: E8.9 195.58,64.77 195.58,69.85 E8.6
N$40
  Bottom 0.254: E8.10 197.49,64.14 194.31,67.31 175.26,67.31 173.35,65.41 E15.11
N$41
  Top 0.254: E40.2 22.86,100.33 22.86,100.97 PAD19.1
N$42  (via drill 0.61)
  Top 0.254: v186.69,89.53 186.69,71.12 193.04,64.77 E8.8
  Bottom 0.254: IC7.7 66.67,93.34 67.94,92.08 163.19,92.08 164.47,93.34 E17.9 165.74,94.61 167,95.89 170.81,95.89 172.09,94.61 E17.12 172.72,92.71 172.72,92.08 173.35,91.44 184.78,91.44 v186.69,89.53
N$43
  Top 0.254: E40.3 20.32,100.33 20.32,100.97 PAD28.1
N$44
  Top 0.254: E24.6 111.12,70.48 109.86,69.22 107.31,69.22 107.31,92.08 99.06,100.33 E32.1
N$45
  Top 0.254: E1.11 223.52,8.89 219.71,12.7 219.71,25.4 218.44,26.67 E2.6
N$46  (via drill 0.61)
  Top 0.254: v45.72,43.18 45.72,46.99 E36.13 | v133.99,6.99 135.89,6.99 137.79,5.08 154.31,5.08 154.31,26.67 158.12,30.48 158.12,66.67 159.38,67.94 159.38,100.97 158.75,101.6 163.19,106.05 165.1,106.05 165.1,102.87 E17.8
  Bottom 0.254: v45.72,43.18 46.99,41.91 46.99,35.56 51.44,35.56 56.52,30.48 56.52,8.89 104.78,8.89 105.41,9.53 131.44,9.53 v133.99,6.99
N$47
  Top 0.254: E19.12 147.32,80.01 146.05,81.28 146.05,87.63 143.51,90.17 141.6,90.17 141.6,89.53 140.97,88.9 140.97,87.63 141.6,87 E19.5
N$48
  Top 0.254: E4.10 218.44,46.99 218.44,52.07 E4.7 | E4.3 227.97,52.7 226.69,52.7 E4.4 226.06,54.61 226.06,57.78 R19.2
  Bottom 0.254: E4.7 219.07,52.7 220.34,51.44 224.16,51.44 225.43,52.7 E4.4
N$49  (via drill 0.61)
  Top 0.254: v191.77,5.71 187.32,10.16 187.32,27.94 184.15,31.11 184.15,39.37 179.07,44.45 176.53,44.45 176.53,55.88 175.26,57.15 E14.4
  Bottom 0.254: E14.5 173.35,57.78 174.62,57.78 E14.4 | v191.77,5.71 224.16,5.71 225.43,6.99 E1.12
N$50
  Top 0.254: E40.4 17.78,100.33 17.78,100.97 PAD29.1
N$51
  Top 0.254: E40.5 15.24,100.33 15.24,100.97 PAD30.1
N$52
  Top 0.254: E40.6 12.7,100.33 12.7,100.97 PAD31.1
N$53
  Top 0.254: E40.7 10.16,100.33 10.16,100.97 PAD32.1
N$54
  Top 0.254: E40.8 7.62,100.33 7.62,100.97 PAD33.1
N$55
  Top 0.254: E40.16 25.4,90.17 25.4,89.53 PAD34.1
N$56
  Top 0.254: E40.15 22.86,90.17 22.86,89.53 PAD35.1
N$57
  Top 0.254: E40.14 20.32,90.17 20.32,89.53 PAD36.1
N$58
  Top 0.254: E40.13 17.78,90.17 17.78,89.53 PAD37.1
N$59
  Top 0.254: E40.12 15.24,90.17 15.24,89.53 PAD38.1
N$60  (via drill 0.61)
  Top 0.254: v81.28,29.84 81.28,31.75 IC2.6 | v121.92,30.48 123.19,31.75 123.19,45.72 124.46,46.99 E23.15
  Bottom 0.254: v81.28,29.84 81.92,30.48 v121.92,30.48
N$61
  Top 0.254: E40.11 12.7,90.17 12.7,89.53 PAD39.1
N$62  (via drill 0.61)
  Top 0.254: v99.69,20.95 99.69,23.5 99.06,24.13 IC4.1
  Bottom 0.254: v99.69,20.95 116.2,20.95 118.75,18.41 E21.13
N$63
  Bottom 0.254: IC3.1 85.72,24.77 80.01,19.05 80.01,15.24 124.46,15.24 125.73,16.51 125.73,19.68 123.83,19.68 122.56,18.41 E21.14
N$64
  Bottom 0.254: IC3.6 81.92,17.14 83.19,15.88 122.56,15.88 123.83,17.14 E21.15
N$65
  Bottom 0.254: IC2.1 87,40.01 89.53,37.47 120.02,37.47 123.83,33.66 E22.15
N$66  (via drill 0.61)
  Top 0.254: v107.31,34.92 106.68,35.56 v106.68,55.88
  Bottom 0.254: v107.31,34.92 117.47,34.92 118.75,33.66 E22.13 | v106.68,55.88 99.69,55.88 IC5.1
N$67  (via drill 0.61)
  Top 0.254: v92.71,36.2 92.71,45.72 93.98,46.99 IC5.6
  Bottom 0.254: v92.71,36.2 118.75,36.2 121.28,33.66 E22.14
N$68
  Top 0.254: E40.10 10.16,90.17 10.16,89.53 PAD40.1
N$69
  Top 0.254: E40.9 7.62,90.17 7.62,89.53 PAD41.1
N$70
  Top 0.254: E39.1 233.68,102.87 233.68,103.5 PAD42.1
N$71
  Top 0.254: E39.2 231.14,102.87 231.14,103.5 PAD43.1
N$72
  Top 0.254: E39.3 228.6,102.87 228.6,103.5 PAD44.1
N$73
  Top 0.254: E39.4 226.06,102.87 226.06,103.5 PAD45.1
N$74
  Top 0.254: E39.5 223.52,102.87 223.52,103.5 PAD46.1
N$75
  Top 0.254: E39.6 220.98,102.87 220.98,103.5 PAD47.1
N$76
  Top 0.254: E39.7 218.44,102.87 218.44,103.5 PAD48.1
N$77
  Top 0.254: E39.8 215.9,102.87 215.9,103.5 PAD49.1
N$78
  Top 0.254: E39.16 233.68,92.71 233.68,92.08 PAD50.1
N$79
  Top 0.254: E39.15 231.14,92.71 231.14,92.08 PAD51.1
N$80
  Top 0.254: E39.14 228.6,92.71 228.6,92.08 PAD52.1
N$81
  Top 0.254: E39.13 226.06,92.71 226.06,92.08 PAD53.1
N$82
  Top 0.254: E39.12 223.52,92.71 223.52,92.08 PAD54.1
N$83
  Top 0.254: E39.11 220.98,92.71 220.98,92.08 PAD55.1
N$84
  Top 0.254: E39.10 218.44,92.71 218.44,92.08 PAD56.1
N$85
  Top 0.254: E39.9 215.9,92.71 215.9,92.08 PAD57.1
N$86  (via drill 0.61)
  Top 0.254: v113.67,109.22 109.86,105.41 100.33,105.41 97.79,102.87 97.79,92.71 95.25,90.17 95.25,77.47 89.53,71.75 E30.5 | v195.58,109.22 201.93,102.87 201.93,81.28 203.2,80.01 IC10.7
  Bottom 0.254: v195.58,109.22 v113.67,109.22
N$87
  Top 0.254: E32.12 93.98,95.25 91.44,97.79 91.44,100.33 E32.4
  Bottom 0.254: E32.5 89.53,100.97 90.81,100.97 E32.4
N$88
  Top 0.254: E6.10 222.88,78.11 221.62,78.11 E6.9 220.98,80.01 220.98,85.09 E6.6
N$89
  Top 0.254: IC10.2 203.84,85.72 205.1,85.72 IC10.1
  Bottom 0.254: E6.3 227.97,85.72 226.69,84.45 213.36,84.45 211.46,86.36 206.38,86.36 IC10.1
N$90  (via drill 0.61)
  Top 0.254: v145.41,66.67 147.32,64.77 E18.12 | v142.88,67.31 142.24,67.94 142.24,69.85 E18.5
  Bottom 0.254: v145.41,66.67 144.78,67.31 v142.88,67.31
N$91
  Top 0.254: E26.12 119.38,95.25 116.84,97.79 116.84,99.06 118.11,100.33 118.11,105.41 115.57,107.95 114.3,107.95 114.3,102.87 E26.5
N$92  (via drill 0.61)
  Top 0.254: v138.43,97.16 138.43,81.28 137.16,80.01 E19.8 | v148.59,97.79 149.86,99.06 149.86,100.33 E20.2
  Bottom 0.254: v138.43,97.16 139.06,97.79 v148.59,97.79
